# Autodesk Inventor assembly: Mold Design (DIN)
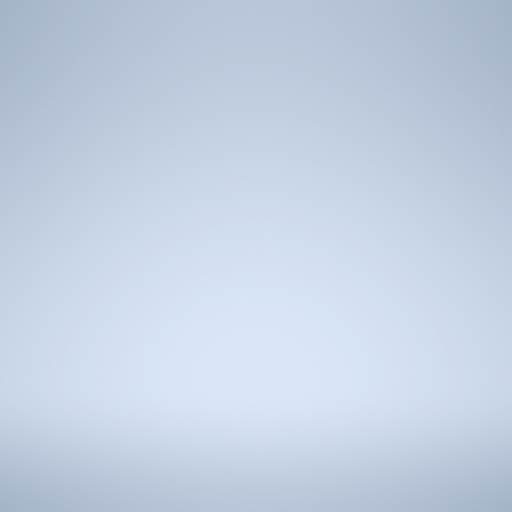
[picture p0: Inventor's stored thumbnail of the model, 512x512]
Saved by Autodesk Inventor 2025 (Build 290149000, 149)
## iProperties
Created: 2002-07
Part Number: Mold Design (DIN)
Document SubType Name: Assembly
Control State: 0
Master: False
Checked Out: False
Shininess: 64.0
Length Units: 11269
Angle Units: 11279
Time Units: 11290
Mass Units: 11283
Length Display Precision: 3
Angle Display Precision: 2
Compacted: True
Density: 0.0
Volumn: 0.0
Area: 0.0
PropertySet Name: Model Information
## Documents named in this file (1)
- C:\Users\enu\Desktop\2\Mold Design (DIN).iam
